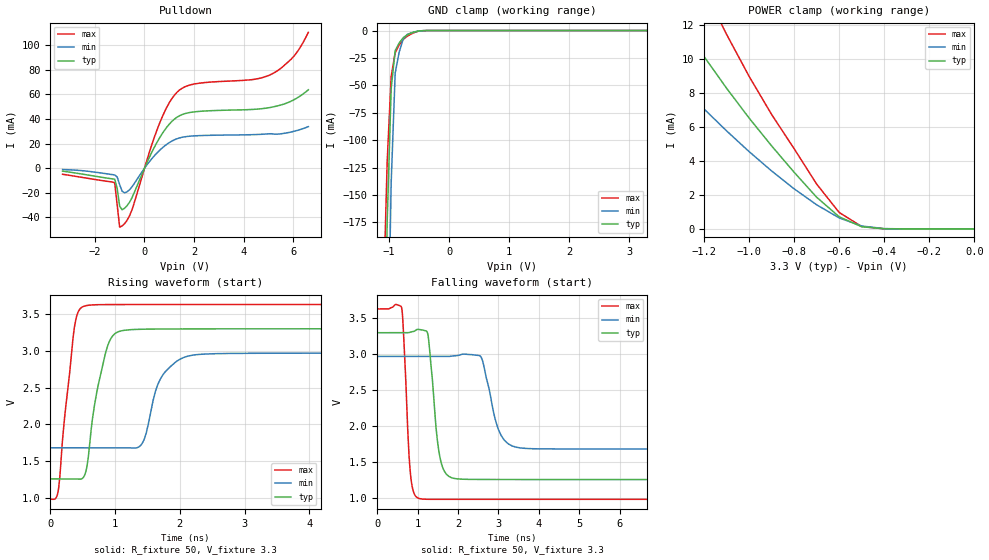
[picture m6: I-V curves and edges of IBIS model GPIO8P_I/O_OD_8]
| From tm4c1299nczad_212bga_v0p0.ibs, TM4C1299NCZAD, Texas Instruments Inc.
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|   Model Cell GPIO8P_I/O_OD_8
[Model]   GPIO8P_I/O_OD_8
Model_type   I/O_open_drain
Polarity   Inverting
Enable   Active-Low
Vinl =  0.8
Vinh =  2
Cref =  15.0000pF
Rref =  100.0000M
Vref =  0V
Vmeas =  1.65
C_comp   5.378567p   4.597605p   6.118031p
[Model Spec]
Vinl   0.8   0.8   0.8
Vinh   2   2   2
[Temperature Range]   25   125   -40
[Voltage Range]   3.3   2.97   3.63
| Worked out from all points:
|   slope of the pulldown table from 0 to 0.495 V, typ, clamps not added: 23.8 ohm
|   GND clamp passes 1 mA (typ) near -0.55 V on its own axis
|   POWER clamp passes 1 mA (typ) near -0.62 V on its own axis
|   rising waveform, R_fixture 50, V_fixture 3.3: 20-80 % time 230ps typ, 276ps min, 176ps max; typ from 1.26 V to 3.3 V
|   falling waveform, R_fixture 50, V_fixture 3.3: 20-80 % time 198ps typ, 327ps min, 129ps max; typ from 3.3 V to 1.26 V
| Nom Voltages:
|   VBAT=3.3, VDDC=1.2, VDD=3.3, GND=0
| Min Voltages:
|   VBAT=2.97, VDDC=1.08, VDD=2.97, GND=0
| Max Voltages:
|   VBAT=3.63, VDDC=1.32, VDD=3.63, GND=0
[POWER_clamp]
|   voltage   I(typ)   I(min)   I(max)
-3.3V     116.1mA    496.8mA    244.3mA
-1.533V   17.14mA    11.87mA    23.97mA
-1.3V     12.14mA    8.433mA    16.92mA
-1.267V   11.48mA    7.98mA     15.99mA
-1.133V   8.919mA    6.212mA    12.36mA
-1.1V     8.296mA    5.781mA    11.47mA
-900mV    4.896mA    3.418mA    6.747mA
-800mV    3.341mA    2.365mA    4.729mA
-700mV    1.867mA    1.423mA    2.643mA
-600mV    716.2uA    650.8uA    969.8uA
-500mV    130.1uA    172.8uA    144.6uA
0V        364.7pA    9.133nA    53.42pA
[Pulldown]
|   voltage   I(typ)   I(min)   I(max)
-3.3V     -2.339mA   -1.013mA   -4.845mA
-1.2V     -8.874mA   -5.43mA    -11.86mA
-1.1V     -16.34mA   -7.084mA   -29.69mA
-1V       -30.87mA   -13.32mA   -47.87mA
-900mV    -33.74mA   -18.66mA   -46.85mA
-500mV    -23.82mA   -14.99mA   -33.55mA
600mV     24.46mA    14.43mA    36.18mA
1.3V      41.39mA    23.95mA    61.62mA
2V        45.85mA    26.35mA    68.5mA
5.1V      49.57mA    28.09mA    76.36mA
6V        55.51mA    29.95mA    90.69mA
6.6V      63.82mA    33.88mA    110.6mA
[GND_clamp]
|   voltage   I(typ)   I(min)   I(max)
-3.3V     -16.39A    -15.37A    -17.22A
-1.1V     -384.9mA   -635.5mA   -255.1mA
-1.033V   -175.3mA   -338.1mA   -120.1mA
-966.7mV  -53.11mA   -139.3mA   -41.82mA
-900mV    -18.35mA   -38.91mA   -20.36mA
-833.3mV  -11.36mA   -19.64mA   -13.17mA
-766.7mV  -6.568mA   -7.874mA   -8.128mA
-700mV    -3.981mA   -3.622mA   -5.248mA
-500mV    -326.7uA   -386.2uA   -372.4uA
-366.7mV  -15.8uA    -32.57uA   -14.68uA
3.3V      364.7pA    3.701uA    29.32pA
[Ramp]
| variable   typ   min   max
dV/dt_f  1.2536972/0.2012073n 0.79277568/0.33071134n   1.62575/0.13201897n
dV/dt_r  1.2600245/0.23437599n 0.89149831/0.39117356n  1.6218591/0.15700656n
R_load = 50
[Rising Waveform]
R_fixture = 50
V_fixture = 3.3
V_fixture_min = 2.97
V_fixture_max = 3.63
|   time   V(typ)   V(min)   V(max)
0s        1.258V     1.681V     982.8mV
129.5ps   1.258V     1.681V     1.135V
390.8ps   1.257V     1.681V     3.413V
576.6ps   1.49V      1.681V     3.618V
866.8ps   3.016V     1.681V     3.629V
1.198ns   3.285V     1.68V      3.63V
1.434ns   3.294V     1.765V     3.63V
1.764ns   3.297V     2.704V     3.63V
2.295ns   3.298V     2.951V     3.63V
20.01ns   3.3V       2.97V      3.63V
[Falling Waveform]
R_fixture = 50
V_fixture = 3.3
V_fixture_min = 2.97
V_fixture_max = 3.63
|   time   V(typ)   V(min)   V(max)
0s        3.3V       2.97V      3.63V
604.5ps   3.3V       2.97V      3.649V
820.3ps   3.308V     2.97V      1.352V
1.056ns   3.343V     2.97V      991.7mV
1.262ns   3.253V     2.97V      983mV
1.552ns   1.568V     2.97V      982.7mV
1.89ns    1.275V     2.978V     982.8mV
2.568ns   1.259V     2.964V     982.8mV
3.541ns   1.258V     1.698V     982.8mV
20.01ns   1.258V     1.681V     982.8mV
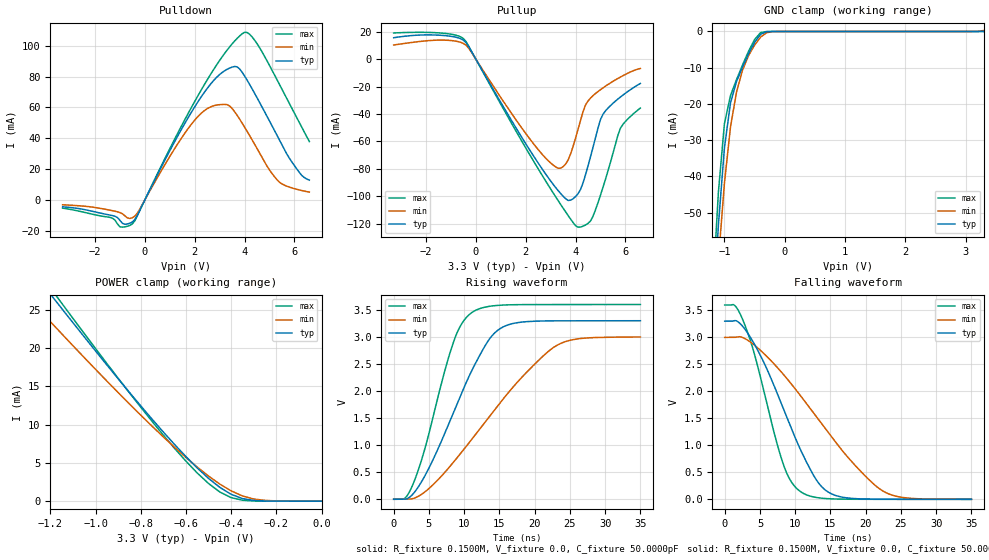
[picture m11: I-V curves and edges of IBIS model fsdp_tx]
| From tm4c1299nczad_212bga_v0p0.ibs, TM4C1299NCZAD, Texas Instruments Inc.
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|   Model fsdp_tx
[Model]   fsdp_tx
Model_type   3-state
Polarity   Non-Inverting
Enable   Active-Low
C_comp   7.0000pF   7.0000pF   7.0000pF
[Model Spec]
Vmeas 1.65 1.5 1.8
[Temperature Range]   27.0000   0.1250k   -40.0000
[Voltage Range]   3.3000V   3.0000V   3.6000V
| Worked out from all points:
|   slope of the pulldown table from 0 to 0.495 V, typ, clamps not added: 30.8 ohm
|   slope of the pullup table from 0 to 0.495 V, typ, clamps not added: 31.5 ohm
|   GND clamp passes 1 mA (typ) near -0.41 V on its own axis
|   POWER clamp passes 1 mA (typ) near -0.41 V on its own axis
|   rising waveform, R_fixture 0.1500M, V_fixture 0.0, C_fixture 50.0000pF: 20-80 % time 6.8ns typ, 11.3ns min, 4.48ns max; typ from 0 V to 3.3 V
|   falling waveform, R_fixture 0.1500M, V_fixture 0.0, C_fixture 50.0000pF: 20-80 % time 6.56ns typ, 11ns min, 4.34ns max; typ from 3.3 V to 0 V
[Pulldown]
|Voltage   I(typ)   I(min)   I(max)
-3.3V     -4.49mA    -3.18mA    -5.372mA
-1.3V     -10.21mA   -7.016mA   -11.87mA
-1V       -13.27mA   -8.238mA   -17.5mA
-500mV    -14.33mA   -11.59mA   -15.56mA
2.3V      67.82mA    56.8mA     72.41mA
3.3V      84.78mA    61.83mA    97.25mA
3.7V      86.41mA    54.97mA    104.8mA
4V        80.5mA     47.29mA    108.8mA
4.5V      66.35mA    33.43mA    101.5mA
5.4V      38.93mA    11.49mA    75.02mA
6.2V      17.82mA    6.445mA    50.17mA
6.6V      12.82mA    5.037mA    37.88mA
[Pullup]
|Voltage	  I(typ)   I(min)   I(max)
-3.3V     15.73mA    10.41mA    19.17mA
-1.6V     17.68mA    13.93mA    19.39mA
-500mV    13.9mA     11.53mA    15.1mA
2V        -61.66mA   -54.17mA   -64.7mA
3.1V      -91.31mA   -77.27mA   -97.58mA
3.6V      -101.8mA   -76.54mA   -111.4mA
4.1V      -98.15mA   -51.11mA   -122.6mA
4.4V      -84.25mA   -33.4mA    -121mA
4.6V      -71.13mA   -28.33mA   -118.1mA
5.1V      -40.19mA   -20.89mA   -93.51mA
5.8V      -27.57mA   -12.99mA   -50.34mA
6.6V      -17.66mA   -6.716mA   -35.62mA
[GND_clamp]
|Voltage	  I(typ)   I(min)   I(max)
-3.3V     -782mA     -691.8mA   -849.7mA
-1.2V     -81.21mA   -87.89mA   -73.74mA
-1.1V     -53.46mA   -63.22mA   -44.36mA
-1V       -32.12mA   -41.94mA   -25.46mA
-900mV    -19.78mA   -26.42mA   -17.7mA
-800mV    -13.86mA   -16.76mA   -13.31mA
-700mV    -9.821mA   -10.67mA   -9.261mA
-600mV    -6.194mA   -6.67mA    -5.473mA
-500mV    -3.012mA   -3.762mA   -2.229mA
-400mV    -781.4uA   -1.558mA   -310.6uA
-200mV    -1.921uA   -32.16uA   -238.5nA
3.3V      198.9nA    275.2uA    240.3nA
[POWER_clamp]
|Voltage	  I(typ)   I(min)   I(max)
-3.3V     128.2mA    118.7mA    139.8mA
-1.3V     30.83mA    26.64mA    31.9mA
-1.25V    28.94mA    25.04mA    29.88mA
-1.2V     27.06mA    23.45mA    27.87mA
-1.15V    25.18mA    21.88mA    25.87mA
-750mV    10.71mA    9.793mA    10.42mA
-600mV    5.81mA     5.697mA    5.218mA
-500mV    2.966mA    3.271mA    2.299mA
-400mV    885uA      1.333mA    454.5uA
-350mV    328.3uA    673uA      118.8uA
-250mV    20.25uA    94.06uA    3.223uA
0V        198.9nA    574.7nA    247.2nA
[Ramp]
| variable   typ   min   max
dV/dt_r		1.9796/6.0022n   1.7995/10.3439n   2.1595/3.6846n
dV/dt_f		1.9796/5.8954n   1.7995/10.1209n   2.1595/3.5960n
R_load =	0.1500M
[Rising Waveform]
R_fixture=	0.1500M
V_fixture=	0.0
V_fixture_min=	0.0
V_fixture_max=	0.0
C_fixture=	50.0000pF
|time   V(typ)   V(min)   V(max)
0s        35.11uV    27.5uV     52.25uV
1.577ns   2.192mV    1.006mV    18.9mV
2.803ns   106.1mV    15.9mV     296mV
4.379ns   420.8mV    131.2mV    911mV
8.408ns   1.58V      673.1mV    2.874V
10.9ns    2.328V     1.077V     3.431V
13.38ns   2.923V     1.496V     3.561V
15.14ns   3.156V     1.788V     3.586V
22.98ns   3.298V     2.831V     3.599V
35ns      3.299V     2.999V     3.599V
[Falling Waveform]
R_fixture=	0.1500M
V_fixture=	0.0
V_fixture_min=	0.0
V_fixture_max=	0.0
C_fixture=	50.0000pF
|time   V(typ)   V(min)   V(max)
0s        3.299V     2.999V     3.599V
1.436ns   3.31V      3V         3.588V
2.733ns   3.175V     2.986V     3.272V
4.239ns   2.868V     2.853V     2.68V
8.163ns   1.733V     2.339V     708.4mV
10.55ns   978.2mV    1.955V     163mV
12.93ns   375.3mV    1.545V     35.73mV
14.68ns   135.3mV    1.242V     11.78mV
22.42ns   1.324mV    155.7mV    310.6uV
35ns      52.66uV    290.4uV    26.4uV
